VERSION 5.8 ;
BUSBITCHARS "[]" ;
DIVIDERCHAR "/" ;
CLEARANCEMEASURE EUCLIDEAN ;

SITE coresite
    SIZE 0.0450 BY 0.1440 ;
    CLASS CORE ;
    SYMMETRY Y ;
END coresite

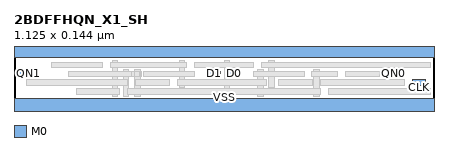
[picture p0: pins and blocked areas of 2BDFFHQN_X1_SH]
MACRO 2BDFFHQN_X1_SH
  CLASS CORE ;
  ORIGIN 0 0 ;
  FOREIGN 2BDFFHQN_X1_SH 0 0 ;
  SIZE 1.1250 BY 0.1440 ;
  SYMMETRY X Y ;
  SITE coresite ;
  PIN QN0
    DIRECTION OUTPUT ;
    USE SIGNAL ;
    PORT
      LAYER M0 ;
        RECT 1.0005 0.0910 1.0350 0.0770 ;
    END
  END QN0
  PIN D0
    DIRECTION INPUT ;
    USE SIGNAL ;
    PORT
      LAYER M0 ;
        RECT 0.5730 0.0910 0.6075 0.0770 ;
    END
  END D0
  PIN D1
    DIRECTION INPUT ;
    USE SIGNAL ;
    PORT
      LAYER M0 ;
        RECT 0.5175 0.0910 0.5520 0.0770 ;
    END
  END D1
  PIN QN1
    DIRECTION OUTPUT ;
    USE SIGNAL ;
    PORT
      LAYER M0 ;
        RECT 0.0105 0.0910 0.0450 0.0770 ;
    END
  END QN1
  PIN CLK
    DIRECTION INPUT ;
    USE SIGNAL ;
    PORT
      LAYER M0 ;
        RECT 1.0680 0.0670 1.1025 0.0530 ;
    END
  END CLK
  PIN VDD
    DIRECTION INOUT ;
    USE POWER ;
    SHAPE ABUTMENT ;
    PORT
      LAYER M0 ;
        RECT 0.0000 0.1260 1.1250 0.1620 ;
    END
  END VDD
  PIN VSS
    DIRECTION INOUT ;
    USE GROUND ;
    SHAPE ABUTMENT ;
    PORT
      LAYER M0 ;
        RECT 0.0000 -0.0180 1.1250 0.0180 ;
    END
  END VSS
  OBS
      LAYER M2 ;
        RECT 0.6480 0.0770 0.7020 0.0910 ;
        RECT 0.2880 0.0770 0.3420 0.0910 ;
      LAYER V0 ;
        RECT 0.6830 0.1010 0.6970 0.1150 ;
        RECT 0.6530 0.0530 0.6670 0.0670 ;
        RECT 0.4430 0.0530 0.4570 0.0670 ;
        RECT 0.4430 0.1010 0.4570 0.1150 ;
        RECT 0.2630 0.0290 0.2770 0.0430 ;
        RECT 0.2630 0.1010 0.2770 0.1150 ;
        RECT 0.8030 0.0290 0.8170 0.0430 ;
        RECT 0.8030 0.0770 0.8170 0.0910 ;
        RECT 0.5630 0.0290 0.5770 0.0430 ;
        RECT 0.5630 0.1010 0.5770 0.1150 ;
        RECT 0.3230 0.0290 0.3370 0.0430 ;
        RECT 0.2930 0.0770 0.3070 0.0910 ;
      LAYER M1 ;
        RECT 0.6825 0.1200 0.6975 0.0480 ;
        RECT 0.5625 0.1200 0.5775 0.0240 ;
        RECT 0.4425 0.1200 0.4575 0.0480 ;
        RECT 0.2625 0.1200 0.2775 0.0240 ;
        RECT 0.8025 0.0960 0.8175 0.0240 ;
        RECT 0.6525 0.0960 0.6675 0.0240 ;
        RECT 0.3225 0.0960 0.3375 0.0240 ;
        RECT 0.2925 0.0960 0.3075 0.0240 ;
      LAYER V1 ;
        RECT 0.6830 0.0770 0.6970 0.0910 ;
        RECT 0.6530 0.0770 0.6670 0.0910 ;
        RECT 0.3230 0.0770 0.3370 0.0910 ;
        RECT 0.2930 0.0770 0.3070 0.0910 ;
      LAYER M0 ;
        RECT 0.6630 0.1010 1.1145 0.1150 ;
        RECT 0.4830 0.1010 0.6420 0.1150 ;
        RECT 0.2580 0.1010 0.4620 0.1150 ;
        RECT 0.1005 0.1010 0.2370 0.1150 ;
        RECT 0.8880 0.0770 0.9795 0.0910 ;
        RECT 0.7980 0.0770 0.8670 0.0910 ;
        RECT 0.6405 0.0770 0.7770 0.0910 ;
        RECT 0.3480 0.0770 0.4845 0.0910 ;
        RECT 0.1455 0.0770 0.3150 0.0910 ;
        RECT 0.8205 0.0530 1.0470 0.0670 ;
        RECT 0.7080 0.0530 0.7995 0.0670 ;
        RECT 0.4380 0.0530 0.6750 0.0670 ;
        RECT 0.3255 0.0530 0.4170 0.0670 ;
        RECT 0.0330 0.0530 0.3045 0.0670 ;
        RECT 0.8430 0.0290 1.1145 0.0430 ;
        RECT 0.3030 0.0290 0.8220 0.0430 ;
        RECT 0.1680 0.0290 0.2820 0.0430 ;
  END
END 2BDFFHQN_X1_SH

END LIBRARY
